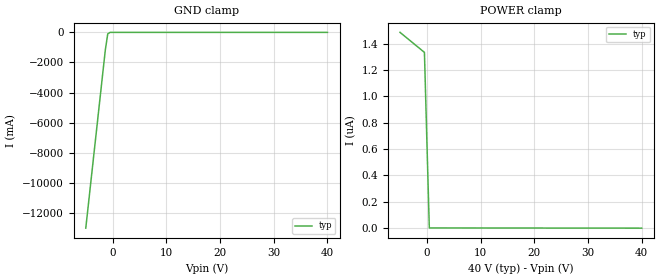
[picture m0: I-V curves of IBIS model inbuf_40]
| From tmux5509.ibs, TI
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| inbuf_40
[Model]   inbuf_40
Model_type   Input
Vinl = 0.7
Vinh = 1.2
|   typ   min   max
C_comp   6.362683e-13   NA   NA
[Voltage Range]   40   NA   NA
[Temperature Range]   27   NA   NA
[Power Clamp Reference]   40   NA   NA
[GND Clamp Reference]   0   NA   NA
[GND Clamp]
|   Voltage   I(typ)   I(min)   I(max)
-5V       -13.02A    NA         NA
-1.364V   -1.178A    NA         NA
-909.1mV  -99.73mA   NA         NA
-454.5mV  -820.3nA   NA         NA
40V       660nA      NA         NA
[POWER Clamp]
|   Voltage   I(typ)   I(min)   I(max)
-5V       1.485uA    NA         NA
-454.5mV  1.333uA    NA         NA
0V        660nA      NA         NA
454.5mV   1.343nA    NA         NA
40V       -162.9pA   NA         NA
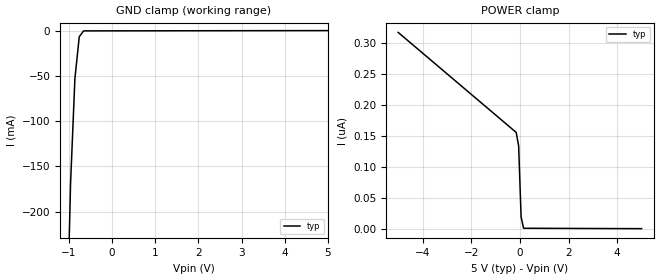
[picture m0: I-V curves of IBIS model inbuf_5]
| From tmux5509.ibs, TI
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| inbuf_5
[Model]   inbuf_5
Model_type   Input
Vinl = 0.7
Vinh = 1.2
|   typ   min   max
C_comp   1.008417e-12   NA   NA
[Voltage Range]   5   NA   NA
[Temperature Range]   27   NA   NA
[Power Clamp Reference]   5   NA   NA
[GND Clamp Reference]   0   NA   NA
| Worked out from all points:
|   GND clamp passes 1 mA (typ) near -0.67 V on its own axis
[GND Clamp]
|   Voltage   I(typ)   I(min)   I(max)
-5V       -13.02A    NA         NA
-1.061V   -368.7mA   NA         NA
-959.6mV  -169.9mA   NA         NA
-858.6mV  -53.22mA   NA         NA
-757.6mV  -6.808mA   NA         NA
-656.6mV  -332.8uA   NA         NA
5V        75.95nA    NA         NA
[POWER Clamp]
|   Voltage   I(typ)   I(min)   I(max)
-5V       317.5nA    NA         NA
-151.5mV  155.7nA    NA         NA
-50.51mV  133.9nA    NA         NA
50.51mV   18.97nA    NA         NA
151.5mV   625.1pA    NA         NA
5V        -23.06pA   NA         NA
